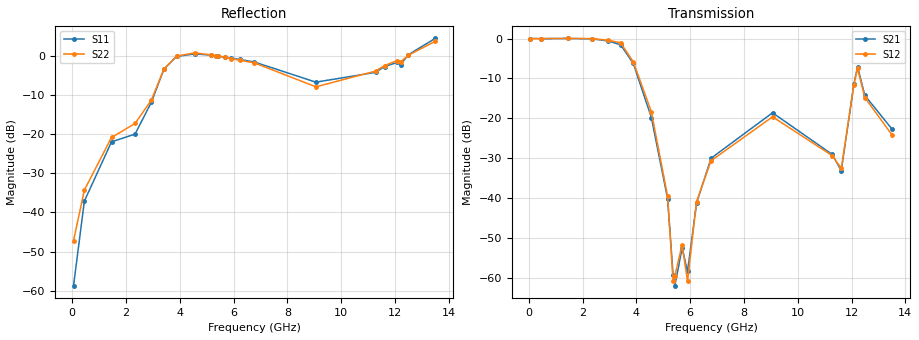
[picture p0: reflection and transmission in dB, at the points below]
! AVX THIN FILM OPERATION
! 0805 Size Low Pass Filter P/N  LP0805A2750AWTR
! Network Analyzer HP8720ES.07.64: Feb 23, 2000 Serial No. US39172382
! Hewlett-Packard
!  2 Feb 2003  05:01:14
! Frequency  S11  S21  S12  S22
# HZ  S  DB R  50
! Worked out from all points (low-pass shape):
!   201 points, 50 MHz to 13.5 GHz, reference 50 ohm
!   highest |S21| = 0.02 dB at 1.462 GHz (marker M1); lowest = -61.9 dB at 5.43 GHz (marker M2)
!   |S21| within 3 dB of the highest: start of sweep to 3.609 GHz
!   lowest |S11| = -58.7 dB at 50 MHz (marker M3), VSWR 1.00, Z = 50 - j0.109 ohm
!   |S11| at or under -10 dB: start of sweep to 3.03 GHz
!   |S22| runs from -49.0 to 3.7 dB; largest |S21 - S12| = 0.05
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5e7  -58.67 -68.9  -0.00 -1.3  -0.03 -1.3  -47.20 19.2
4.535e8  -37.09 -128.4  -0.02 -11.8  -0.04 -12.0  -34.28 -122.5
1.46225e9  -21.98 153.4  0.02 -40.2  0.04 -40.6  -20.87 153.6
2.3365e9  -20.02 62.9  -0.07 -73.3  -0.03 -73.1  -17.30 50.4
2.94175e9  -11.92 -68.5  -0.60 -104.8  -0.42 -104.5  -11.38 -73.1
3.4125e9  -3.44 -137.1  -1.57 -140.5  -1.07 -141.2  -3.38 -133.0
3.88325e9  -0.20 163.6  -6.24 171.3  -5.82 169.0  -0.11 167.7
4.55575e9  0.45 106.6  -19.80 124.2  -18.33 125.8  0.72 107.6
5.161e9  0.13 70.7  -40.19 110.5  -39.53 105.5  0.19 70.5
5.36275e9  -0.03 60.0  -59.10 133.4  -60.76 135.9  -0.01 59.9
5.43e9  -0.14 56.6  -61.87 -115.6  -59.43 -114.7  -0.05 56.5
5.699e9  -0.38 43.6  -52.45 -80.4  -51.57 -86.4  -0.43 44.1
5.90075e9  -0.61 34.2  -58.28 15.3  -60.80 -15.3  -0.73 34.3
6.237e9  -0.97 19.0  -41.17 68.5  -40.80 66.0  -1.17 19.7
6.775e9  -1.62 -3.9  -29.97 61.5  -30.59 59.8  -1.84 -3.1
9.0615e9  -6.76 -98.4  -18.59 33.7  -19.60 24.9  -7.95 -104.2
1.128075e10  -4.26 126.6  -29.01 -62.3  -29.31 -65.7  -3.95 123.6
1.1617e10  -2.78 114.6  -33.09 -149.4  -32.50 -146.1  -2.52 111.4
1.208775e10  -1.74 95.7  -11.39 122.2  -11.52 124.9  -1.26 94.2
1.222225e10  -2.27 97.2  -7.03 54.1  -7.46 58.2  -1.54 91.3
1.249125e10  0.20 97.1  -14.23 -8.7  -14.77 -1.1  0.08 93.1
1.35e10  4.41 81.5  -22.64 -48.1  -24.09 -43.3  3.66 80.6
